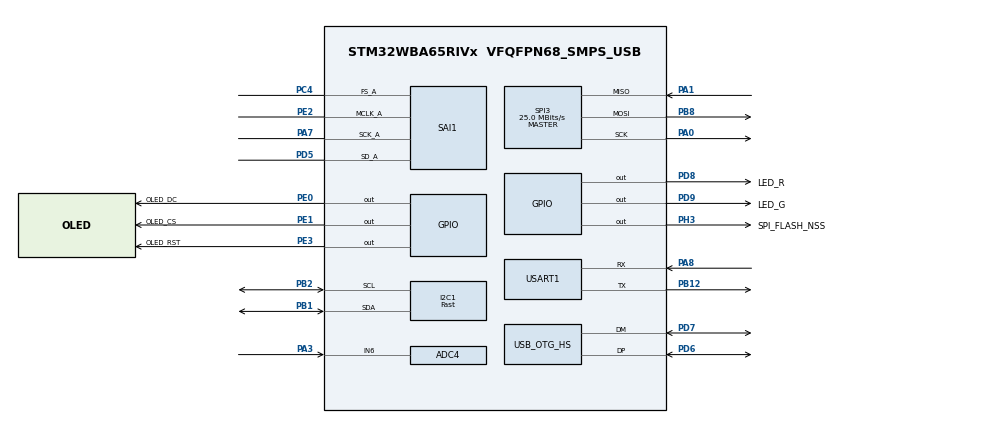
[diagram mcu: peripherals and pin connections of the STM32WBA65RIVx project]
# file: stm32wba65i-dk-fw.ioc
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ADC4.Channel-0\#ChannelRegularConversion=ADC_CHANNEL_6
ADC4.ContinuousConvMode=ENABLE
ADC4.DMAContinuousRequests=ENABLE
ADC4.NbrOfConversionFlag=1
ADC4.OversamplingMode=ENABLE
ADC4.Rank-0\#ChannelRegularConversion=1
ADC4.Ratio=ADC_OVERSAMPLING_RATIO_16
ADC4.RightBitShift=ADC_RIGHTBITSHIFT_4
ADC4.SamplingTime-0\#ChannelRegularConversion=ADC_SAMPLINGTIME_COMMON_1
ADC4.SamplingTimeCommon1=ADC_SAMPLETIME_79CYCLES_5
ADC4.SelectedChannel=ADC_CHANNEL_6
CORTEX_M33_NS.userName=CORTEX_M33
GPDMA1.CIRCULARMODE_GPDMACH0=ENABLE
GPDMA1.CIRCULARMODE_GPDMACH2=ENABLE
GPDMA1.CIRCULARMODE_GPDMACH3=ENABLE
GPDMA1.DESTDATAWIDTH_GPDMACH2=DMA_DEST_DATAWIDTH_HALFWORD
GPDMA1.DESTDATAWIDTH_GPDMACH3=DMA_DEST_DATAWIDTH_HALFWORD
GPDMA1.DESTINC_GPDMACH0=DMA_DINC_INCREMENTED
GPDMA1.DESTINC_GPDMACH1=DMA_DINC_INCREMENTED
GPDMA1.DESTINC_GPDMACH2=DMA_DINC_INCREMENTED
GPDMA1.DIRECTION_GPDMACH1=DMA_PERIPH_TO_MEMORY
GPDMA1.DIRECTION_GPDMACH3=DMA_MEMORY_TO_PERIPH
GPDMA1.DMAHANDLE_GPDMACH3=hdmatx
GPDMA1.IPHANDLE_GPDMACH0-SIMPLEREQUEST_GPDMACH0=__NULL
GPDMA1.IPHANDLE_GPDMACH1-SIMPLEREQUEST_GPDMACH1=__NULL
GPDMA1.IPHANDLE_GPDMACH2-SIMPLEREQUEST_GPDMACH2=__NULL
GPDMA1.IPHANDLE_GPDMACH3-SIMPLEREQUEST_GPDMACH3=__NULL
GPDMA1.REQUEST_GPDMACH0=GPDMA1_REQUEST_USART1_RX
GPDMA1.REQUEST_GPDMACH1=GPDMA1_REQUEST_SPI3_RX
GPDMA1.REQUEST_GPDMACH2=GPDMA1_REQUEST_ADC4
GPDMA1.REQUEST_GPDMACH3=GPDMA1_REQUEST_SAI1_A
GPDMA1.SRCDATAWIDTH_GPDMACH2=DMA_SRC_DATAWIDTH_HALFWORD
GPDMA1.SRCDATAWIDTH_GPDMACH3=DMA_SRC_DATAWIDTH_HALFWORD
GPDMA1.SRCINC_GPDMACH1=DMA_SINC_FIXED
GPDMA1.SRCINC_GPDMACH3=DMA_SINC_INCREMENTED
I2C1.I2C_Speed_Mode=I2C_Fast
I2C1.Timing=0x009034B6
Mcu.Family=STM32WBA
Mcu.Name=STM32WBA65RIVx
Mcu.Package=VFQFPN68_SMPS_USB
NVIC.GPDMA1_Channel1_IRQn=true\:5\:0\:true\:false\:true\:true\:true\:true
NVIC.GPDMA1_Channel3_IRQn=true\:5\:0\:true\:false\:true\:true\:true\:true
NVIC.PriorityGroup=NVIC_PRIORITYGROUP_4
NVIC.SAI1_IRQn=true\:5\:0\:true\:false\:true\:true\:true\:true
NVIC.SPI3_IRQn=true\:5\:0\:true\:false\:true\:true\:true\:true
NVIC.USB_OTG_HS_IRQn=true\:5\:0\:true\:false\:true\:true\:true\:true
OSC_IN.Mode=HSE-External-Oscillator
OSC_IN.Signal=RCC_OSC_IN
OSC_OUT.Mode=HSE-External-Oscillator
OSC_OUT.Signal=RCC_OSC_OUT
PA0.GPIO_Speed=GPIO_SPEED_FREQ_HIGH
PA0.Mode=Full_Duplex_Master
PA0.Signal=SPI3_SCK
PA1.GPIO_Speed=GPIO_SPEED_FREQ_HIGH
PA1.Mode=Full_Duplex_Master
PA1.Signal=SPI3_MISO
PA13(JTSM/SWDIO).Mode=Serial_Wire
PA13(JTSM/SWDIO).Signal=DEBUG_JTMS-SWDIO
PA14(JTCK/SWCLK).Mode=Serial_Wire
PA14(JTCK/SWCLK).Signal=DEBUG_JTCK-SWCLK
PA3.Mode=IN6
PA3.Signal=ADC4_IN6
PA7.Mode=SAI_A_MasterWithClock
PA7.Signal=SAI1_SCK_A
PA8.Mode=Asynchronous
PA8.Signal=USART1_RX
PB1.Mode=I2C
PB1.Signal=I2C1_SDA
PB12.Mode=Asynchronous
PB12.Signal=USART1_TX
PB2.Mode=I2C
PB2.Signal=I2C1_SCL
PB8.GPIO_Speed=GPIO_SPEED_FREQ_HIGH
PB8.Mode=Full_Duplex_Master
PB8.Signal=SPI3_MOSI
PC14-OSC32_IN.Mode=LSE-External-Oscillator
PC14-OSC32_IN.Signal=RCC_OSC32_IN
PC15-OSC32_OUT.Mode=LSE-External-Oscillator
PC15-OSC32_OUT.Signal=RCC_OSC32_OUT
PC4.Mode=SAI_A_MasterWithClock
PC4.Signal=SAI1_FS_A
PD5.GPIO_Speed=GPIO_SPEED_FREQ_HIGH
PD5.Mode=SAI_A_MasterWithClock
PD5.Signal=SAI1_SD_A
PD6.Mode=Internal_Phy_Device
PD6.Signal=USB_OTG_HS_DP
PD7.Mode=Internal_Phy_Device
PD7.Signal=USB_OTG_HS_DM
PD8.GPIO_Label=LED_R
PD8.PinState=GPIO_PIN_SET
PD8.Signal=GPIO_Output
PD9.GPIO_Label=LED_G
PD9.PinState=GPIO_PIN_SET
PD9.Signal=GPIO_Output
PE0.GPIO_Label=OLED_DC
PE0.GPIO_Speed=GPIO_SPEED_FREQ_HIGH
PE0.PinState=GPIO_PIN_SET
PE0.Signal=GPIO_Output
PE1.GPIO_Label=OLED_CS
PE1.GPIO_Speed=GPIO_SPEED_FREQ_HIGH
PE1.PinState=GPIO_PIN_SET
PE1.Signal=GPIO_Output
PE2.Mode=SAI_A_MasterWithClock
PE2.Signal=SAI1_MCLK_A
PE3.GPIO_Label=OLED_RST
PE3.GPIO_Speed=GPIO_SPEED_FREQ_HIGH
PE3.PinState=GPIO_PIN_SET
PE3.Signal=GPIO_Output
PH3-BOOT0.GPIO_Label=SPI_FLASH_NSS
PH3-BOOT0.GPIO_Speed=GPIO_SPEED_FREQ_HIGH
PH3-BOOT0.PinState=GPIO_PIN_SET
PH3-BOOT0.Signal=GPIO_Output
ProjectManager.HeapSize=0x200
ProjectManager.StackSize=0x400
ProjectManager.TargetToolchain=CMake
RCC.ADCFreq_Value=100000000
RCC.AHB5CLKDivider=DIV4
RCC.AHBFreq_Value=100000000
RCC.APB1Freq_Value=100000000
RCC.APB1TimFreq_Value=100000000
RCC.APB2Freq_Value=100000000
RCC.APB2TimFreq_Value=100000000
RCC.CortexFreq_Value=12500000
RCC.HCLKFreq_Value=100000000
RCC.HSE_VALUE=32000000
RCC.HSI_VALUE=16000000
RCC.LSI1_VALUE=32000
RCC.LSI2_VALUE=32000
RCC.PLLFRACN=4096
RCC.PLLM=2
RCC.PLLN=12
RCC.PLLSourceVirtual=RCC_PLLSOURCE_HSE
RCC.SAI1CLockSelection=RCC_SAI1CLKSOURCE_PLL1Q
RCC.SYSCLKFreq_VALUE=100000000
RCC.SYSCLKSourceVirtual=RCC_SYSCLKSOURCE_PLLCLK
RCC.VCOOutputFreq_Value=200000000
SAI1.AudioFrequency-SAI_A_MasterWithClock=SAI_AUDIO_FREQUENCY_16K
SAI1.ErrorAudioFreq-SAI_A_MasterWithClock=1.72 %
SAI1.InitProtocol-SAI_A_MasterWithClock=Enable
SAI1.Instance-SAI_A_MasterWithClock=SAI$Index_Block_A
SAI1.MckOutput=SAI_MCK_OUTPUT_ENABLE
SAI1.NoDivider-SAI_A_MasterWithClock=SAI_MASTERDIVIDER_ENABLE
SAI1.OutputDrive-SAI_A_MasterWithClock=SAI_OUTPUTDRIVE_DISABLE
SAI1.RealAudioFreq-SAI_A_MasterWithClock=16.276 KHz
SAI1.VirtualMode-SAI_A_MasterWithClock=VM_MASTER
SAI1.VirtualProtocol-SAI_A_BASIC=VM_BASIC_PROTOCOL
SPI3.BaudRatePrescaler=SPI_BAUDRATEPRESCALER_4
SPI3.CalculateBaudRate=25.0 MBits/s
SPI3.Direction=SPI_DIRECTION_2LINES
SPI3.FifoThreshold=SPI_FIFO_THRESHOLD_01DATA
SPI3.Mode=SPI_MODE_MASTER
SPI3.VirtualType=VM_MASTER
USART1.VirtualMode-Asynchronous=VM_ASYNC
USB_OTG_HS.RefClockSelection=SYSCFG_OTG_HS_PHY_CLK_SELECT_6
USB_OTG_HS.Sof_enable=DISABLE
USB_OTG_HS.VirtualMode=Device_HS
VP_CORTEX_M33_NS_VS_Hclk.Mode=Hclk_Mode
VP_GPDMA1_VS_GPDMACH0.Mode=SIMPLEREQUEST_GPDMACH0
VP_GPDMA1_VS_GPDMACH1.Mode=SIMPLEREQUEST_GPDMACH1
VP_GPDMA1_VS_GPDMACH2.Mode=SIMPLEREQUEST_GPDMACH2
VP_GPDMA1_VS_GPDMACH3.Mode=SIMPLEREQUEST_GPDMACH3
VP_ICACHE_VS_ICACHE.Mode=DefaultMode
VP_MEMORYMAP_VS_MEMORYMAP.Mode=CurAppReg
VP_PWR_VS_SECSignals.Mode=Security/Privilege
VP_SAI1_VP_$IpInstance_SAIA_SAI_BASIC.Mode=SAI_A_BASIC
board=custom

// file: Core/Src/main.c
/* USER CODE BEGIN Header */
/**
  ******************************************************************************
  * @file           : main.c
  * @brief          : Main program body
  ******************************************************************************
  * @attention
  *
  * Copyright (c) 2025 STMicroelectronics.
  * All rights reserved.
  *
  * This software is licensed under terms that can be found in the LICENSE file
  * in the root directory of this software component.
  * If no LICENSE file comes with this software, it is provided AS-IS.
  *
  ******************************************************************************
  */
/* USER CODE END Header */
#include "main.h"

/* USER CODE BEGIN Includes */
#include "ap.h"
/* USER CODE END Includes */

ADC_HandleTypeDef hadc4;
DMA_NodeTypeDef Node_GPDMA1_Channel2;
DMA_QListTypeDef List_GPDMA1_Channel2;
DMA_HandleTypeDef handle_GPDMA1_Channel2;

I2C_HandleTypeDef hi2c1;

SAI_HandleTypeDef hsai_BlockA1;
DMA_NodeTypeDef Node_GPDMA1_Channel3;
DMA_QListTypeDef List_GPDMA1_Channel3;
DMA_HandleTypeDef handle_GPDMA1_Channel3;

SPI_HandleTypeDef hspi3;
DMA_HandleTypeDef handle_GPDMA1_Channel1;

UART_HandleTypeDef huart1;
DMA_NodeTypeDef Node_GPDMA1_Channel0;
DMA_QListTypeDef List_GPDMA1_Channel0;
DMA_HandleTypeDef handle_GPDMA1_Channel0;

PCD_HandleTypeDef hpcd_USB_OTG_HS;

void SystemClock_Config(void);
static void MX_GPIO_Init(void);
static void MX_GPDMA1_Init(void);
static void MX_ICACHE_Init(void);
static void MX_USART1_UART_Init(void);
static void MX_USB_OTG_HS_PCD_Init(void);
static void MX_SPI3_Init(void);
static void MX_ADC4_Init(void);
static void MX_I2C1_Init(void);
static void MX_SAI1_Init(void);

int main(void)
{

  /* MCU Configuration--------------------------------------------------------*/

  /* Reset of all peripherals, Initializes the Flash interface and the Systick. */
  HAL_Init();

  /* Configure the system clock */
  SystemClock_Config();

  /* Initialize all configured peripherals */
  MX_GPIO_Init();
  MX_GPDMA1_Init();
  MX_ICACHE_Init();
  MX_USART1_UART_Init();
  MX_USB_OTG_HS_PCD_Init();
  MX_SPI3_Init();
  MX_ADC4_Init();
  MX_I2C1_Init();
  MX_SAI1_Init();
  /* USER CODE BEGIN 2 */

  hwInit();
  apInit();
  apMain();

  /* USER CODE END 2 */

  /* Infinite loop */
  while (1)
  {

  }
}

void SystemClock_Config(void)
{
  RCC_OscInitTypeDef RCC_OscInitStruct = {0};
  RCC_ClkInitTypeDef RCC_ClkInitStruct = {0};

  /** Supply configuration update enable
  */
  HAL_PWREx_ConfigSupply(PWR_LDO_SUPPLY);

  /** Configure the main internal regulator output voltage
  */
  if (HAL_PWREx_ControlVoltageScaling(PWR_REGULATOR_VOLTAGE_SCALE1) != HAL_OK)
  {
    Error_Handler();
  }

  /** Initializes the CPU, AHB and APB busses clocks
  */
  RCC_OscInitStruct.OscillatorType = RCC_OSCILLATORTYPE_HSI|RCC_OSCILLATORTYPE_HSE;
  RCC_OscInitStruct.HSEState = RCC_HSE_ON;
  RCC_OscInitStruct.HSEDiv = RCC_HSE_DIV1;
  RCC_OscInitStruct.HSIState = RCC_HSI_ON;
  RCC_OscInitStruct.HSICalibrationValue = RCC_HSICALIBRATION_DEFAULT;
  RCC_OscInitStruct.PLL1.PLLState = RCC_PLL_ON;
  RCC_OscInitStruct.PLL1.PLLSource = RCC_PLLSOURCE_HSE;
  RCC_OscInitStruct.PLL1.PLLM = 2;
  RCC_OscInitStruct.PLL1.PLLN = 12;
  RCC_OscInitStruct.PLL1.PLLP = 2;
  RCC_OscInitStruct.PLL1.PLLQ = 2;
  RCC_OscInitStruct.PLL1.PLLR = 2;
  RCC_OscInitStruct.PLL1.PLLFractional = 4096;
  if (HAL_RCC_OscConfig(&RCC_OscInitStruct) != HAL_OK)
  {
    Error_Handler();
  }

  /** Initializes the CPU, AHB and APB busses clocks
  */
  RCC_ClkInitStruct.ClockType = RCC_CLOCKTYPE_HCLK|RCC_CLOCKTYPE_SYSCLK
                              |RCC_CLOCKTYPE_PCLK1|RCC_CLOCKTYPE_PCLK2
                              |RCC_CLOCKTYPE_PCLK7|RCC_CLOCKTYPE_HCLK5;
  RCC_ClkInitStruct.SYSCLKSource = RCC_SYSCLKSOURCE_PLLCLK;
  RCC_ClkInitStruct.AHBCLKDivider = RCC_SYSCLK_DIV1;
  RCC_ClkInitStruct.APB1CLKDivider = RCC_HCLK_DIV1;
  RCC_ClkInitStruct.APB2CLKDivider = RCC_HCLK_DIV1;
  RCC_ClkInitStruct.APB7CLKDivider = RCC_HCLK_DIV1;
  RCC_ClkInitStruct.AHB5_PLL1_CLKDivider = RCC_SYSCLK_PLL1_DIV4;
  RCC_ClkInitStruct.AHB5_HSEHSI_CLKDivider = RCC_SYSCLK_HSEHSI_DIV1;

  if (HAL_RCC_ClockConfig(&RCC_ClkInitStruct, FLASH_LATENCY_3) != HAL_OK)
  {
    Error_Handler();
  }
}

static void MX_ADC4_Init(void)
{

  ADC_ChannelConfTypeDef sConfig = {0};

  /** Common config
  */
  hadc4.Instance = ADC4;
  hadc4.Init.ClockPrescaler = ADC_CLOCK_ASYNC_DIV1;
  hadc4.Init.Resolution = ADC_RESOLUTION_12B;
  hadc4.Init.DataAlign = ADC_DATAALIGN_RIGHT;
  hadc4.Init.ScanConvMode = ADC_SCAN_DISABLE;
  hadc4.Init.EOCSelection = ADC_EOC_SINGLE_CONV;
  hadc4.Init.LowPowerAutoPowerOff = DISABLE;
  hadc4.Init.LowPowerAutonomousDPD = ADC_LP_AUTONOMOUS_DPD_DISABLE;
  hadc4.Init.LowPowerAutoWait = DISABLE;
  hadc4.Init.ContinuousConvMode = ENABLE;
  hadc4.Init.NbrOfConversion = 1;
  hadc4.Init.ExternalTrigConv = ADC_SOFTWARE_START;
  hadc4.Init.ExternalTrigConvEdge = ADC_EXTERNALTRIGCONVEDGE_NONE;
  hadc4.Init.DMAContinuousRequests = ENABLE;
  hadc4.Init.TriggerFrequencyMode = ADC_TRIGGER_FREQ_LOW;
  hadc4.Init.Overrun = ADC_OVR_DATA_PRESERVED;
  hadc4.Init.SamplingTimeCommon1 = ADC_SAMPLETIME_79CYCLES_5;
  hadc4.Init.SamplingTimeCommon2 = ADC_SAMPLETIME_1CYCLE_5;
  hadc4.Init.OversamplingMode = ENABLE;
  hadc4.Init.Oversampling.Ratio = ADC_OVERSAMPLING_RATIO_16;
  hadc4.Init.Oversampling.RightBitShift = ADC_RIGHTBITSHIFT_4;
  hadc4.Init.Oversampling.TriggeredMode = ADC_TRIGGEREDMODE_SINGLE_TRIGGER;
  if (HAL_ADC_Init(&hadc4) != HAL_OK)
  {
    Error_Handler();
  }

  /** Configure Regular Channel
  */
  sConfig.Channel = ADC_CHANNEL_6;
  sConfig.Rank = ADC_REGULAR_RANK_1;
  sConfig.SamplingTime = ADC_SAMPLINGTIME_COMMON_1;
  if (HAL_ADC_ConfigChannel(&hadc4, &sConfig) != HAL_OK)
  {
    Error_Handler();
  }

}

static void MX_GPDMA1_Init(void)
{

  /* Peripheral clock enable */
  __HAL_RCC_GPDMA1_CLK_ENABLE();

  /* GPDMA1 interrupt Init */
    HAL_NVIC_SetPriority(GPDMA1_Channel1_IRQn, 5, 0);
    HAL_NVIC_EnableIRQ(GPDMA1_Channel1_IRQn);
    HAL_NVIC_SetPriority(GPDMA1_Channel3_IRQn, 5, 0);
    HAL_NVIC_EnableIRQ(GPDMA1_Channel3_IRQn);

}

static void MX_I2C1_Init(void)
{

  hi2c1.Instance = I2C1;
  hi2c1.Init.Timing = 0x009034B6;
  hi2c1.Init.OwnAddress1 = 0;
  hi2c1.Init.AddressingMode = I2C_ADDRESSINGMODE_7BIT;
  hi2c1.Init.DualAddressMode = I2C_DUALADDRESS_DISABLE;
  hi2c1.Init.OwnAddress2 = 0;
  hi2c1.Init.OwnAddress2Masks = I2C_OA2_NOMASK;
  hi2c1.Init.GeneralCallMode = I2C_GENERALCALL_DISABLE;
  hi2c1.Init.NoStretchMode = I2C_NOSTRETCH_DISABLE;
  if (HAL_I2C_Init(&hi2c1) != HAL_OK)
  {
    Error_Handler();
  }

  /** Configure Analogue filter
  */
  if (HAL_I2CEx_ConfigAnalogFilter(&hi2c1, I2C_ANALOGFILTER_ENABLE) != HAL_OK)
  {
    Error_Handler();
  }

  /** Configure Digital filter
  */
  if (HAL_I2CEx_ConfigDigitalFilter(&hi2c1, 0) != HAL_OK)
  {
    Error_Handler();
  }

}

static void MX_ICACHE_Init(void)
{

  /** Enable instruction cache (default 2-ways set associative cache)
  */
  if (HAL_ICACHE_Enable() != HAL_OK)
  {
    Error_Handler();
  }

}

static void MX_SAI1_Init(void)
{

  hsai_BlockA1.Instance = SAI1_Block_A;
  hsai_BlockA1.Init.AudioMode = SAI_MODEMASTER_TX;
  hsai_BlockA1.Init.Synchro = SAI_ASYNCHRONOUS;
  hsai_BlockA1.Init.OutputDrive = SAI_OUTPUTDRIVE_DISABLE;
  hsai_BlockA1.Init.NoDivider = SAI_MASTERDIVIDER_ENABLE;
  hsai_BlockA1.Init.FIFOThreshold = SAI_FIFOTHRESHOLD_EMPTY;
  hsai_BlockA1.Init.AudioFrequency = SAI_AUDIO_FREQUENCY_16K;
  hsai_BlockA1.Init.SynchroExt = SAI_SYNCEXT_DISABLE;
  hsai_BlockA1.Init.MckOutput = SAI_MCK_OUTPUT_ENABLE;
  hsai_BlockA1.Init.MonoStereoMode = SAI_STEREOMODE;
  hsai_BlockA1.Init.CompandingMode = SAI_NOCOMPANDING;
  hsai_BlockA1.Init.TriState = SAI_OUTPUT_NOTRELEASED;
  if (HAL_SAI_InitProtocol(&hsai_BlockA1, SAI_I2S_STANDARD, SAI_PROTOCOL_DATASIZE_16BIT, 2) != HAL_OK)
  {
    Error_Handler();
  }

}

static void MX_SPI3_Init(void)
{

  SPI_AutonomousModeConfTypeDef HAL_SPI_AutonomousMode_Cfg_Struct = {0};

  /* SPI3 parameter configuration*/
  hspi3.Instance = SPI3;
  hspi3.Init.Mode = SPI_MODE_MASTER;
  hspi3.Init.Direction = SPI_DIRECTION_2LINES;
  hspi3.Init.DataSize = SPI_DATASIZE_8BIT;
  hspi3.Init.CLKPolarity = SPI_POLARITY_LOW;
  hspi3.Init.CLKPhase = SPI_PHASE_1EDGE;
  hspi3.Init.NSS = SPI_NSS_SOFT;
  hspi3.Init.BaudRatePrescaler = SPI_BAUDRATEPRESCALER_4;
  hspi3.Init.FirstBit = SPI_FIRSTBIT_MSB;
  hspi3.Init.TIMode = SPI_TIMODE_DISABLE;
  hspi3.Init.CRCCalculation = SPI_CRCCALCULATION_DISABLE;
  hspi3.Init.CRCPolynomial = 0x7;
  hspi3.Init.NSSPMode = SPI_NSS_PULSE_ENABLE;
  hspi3.Init.NSSPolarity = SPI_NSS_POLARITY_LOW;
  hspi3.Init.FifoThreshold = SPI_FIFO_THRESHOLD_01DATA;
  hspi3.Init.MasterSSIdleness = SPI_MASTER_SS_IDLENESS_00CYCLE;
  hspi3.Init.MasterInterDataIdleness = SPI_MASTER_INTERDATA_IDLENESS_00CYCLE;
  hspi3.Init.MasterReceiverAutoSusp = SPI_MASTER_RX_AUTOSUSP_DISABLE;
  hspi3.Init.MasterKeepIOState = SPI_MASTER_KEEP_IO_STATE_DISABLE;
  hspi3.Init.IOSwap = SPI_IO_SWAP_DISABLE;
  hspi3.Init.ReadyMasterManagement = SPI_RDY_MASTER_MANAGEMENT_INTERNALLY;
  hspi3.Init.ReadyPolarity = SPI_RDY_POLARITY_HIGH;
  if (HAL_SPI_Init(&hspi3) != HAL_OK)
  {
    Error_Handler();
  }
  HAL_SPI_AutonomousMode_Cfg_Struct.TriggerState = SPI_AUTO_MODE_DISABLE;
  if (HAL_SPIEx_SetConfigAutonomousMode(&hspi3, &HAL_SPI_AutonomousMode_Cfg_Struct) != HAL_OK)
  {
    Error_Handler();
  }

}

static void MX_USART1_UART_Init(void)
{

  huart1.Instance = USART1;
  huart1.Init.BaudRate = 115200;
  huart1.Init.WordLength = UART_WORDLENGTH_8B;
  huart1.Init.StopBits = UART_STOPBITS_1;
  huart1.Init.Parity = UART_PARITY_NONE;
  huart1.Init.Mode = UART_MODE_TX_RX;
  huart1.Init.HwFlowCtl = UART_HWCONTROL_NONE;
  huart1.Init.OverSampling = UART_OVERSAMPLING_16;
  huart1.Init.OneBitSampling = UART_ONE_BIT_SAMPLE_DISABLE;
  huart1.Init.ClockPrescaler = UART_PRESCALER_DIV1;
  huart1.AdvancedInit.AdvFeatureInit = UART_ADVFEATURE_NO_INIT;
  if (HAL_UART_Init(&huart1) != HAL_OK)
  {
    Error_Handler();
  }
  if (HAL_UARTEx_SetTxFifoThreshold(&huart1, UART_TXFIFO_THRESHOLD_1_8) != HAL_OK)
  {
    Error_Handler();
  }
  if (HAL_UARTEx_SetRxFifoThreshold(&huart1, UART_RXFIFO_THRESHOLD_1_8) != HAL_OK)
  {
    Error_Handler();
  }
  if (HAL_UARTEx_DisableFifoMode(&huart1) != HAL_OK)
  {
    Error_Handler();
  }

}

static void MX_USB_OTG_HS_PCD_Init(void)
{

  hpcd_USB_OTG_HS.Instance = USB_OTG_HS;
  hpcd_USB_OTG_HS.Init.dev_endpoints = 9;
  hpcd_USB_OTG_HS.Init.speed = PCD_SPEED_HIGH;
  hpcd_USB_OTG_HS.Init.phy_itface = USB_OTG_HS_EMBEDDED_PHY;
  hpcd_USB_OTG_HS.Init.Sof_enable = DISABLE;
  hpcd_USB_OTG_HS.Init.low_power_enable = DISABLE;
  hpcd_USB_OTG_HS.Init.lpm_enable = DISABLE;
  hpcd_USB_OTG_HS.Init.use_dedicated_ep1 = DISABLE;
  hpcd_USB_OTG_HS.Init.vbus_sensing_enable = DISABLE;
  hpcd_USB_OTG_HS.Init.dma_enable = DISABLE;
  if (HAL_PCD_Init(&hpcd_USB_OTG_HS) != HAL_OK)
  {
    Error_Handler();
  }

}

static void MX_GPIO_Init(void)
{
  GPIO_InitTypeDef GPIO_InitStruct = {0};

  /* GPIO Ports Clock Enable */
  __HAL_RCC_GPIOB_CLK_ENABLE();
  __HAL_RCC_GPIOA_CLK_ENABLE();
  __HAL_RCC_GPIOD_CLK_ENABLE();
  __HAL_RCC_GPIOC_CLK_ENABLE();
  __HAL_RCC_GPIOE_CLK_ENABLE();
  __HAL_RCC_GPIOH_CLK_ENABLE();

  /*Configure GPIO pin Output Level */
  HAL_GPIO_WritePin(GPIOD, LED_G_Pin|LED_R_Pin, GPIO_PIN_SET);

  /*Configure GPIO pin Output Level */
  HAL_GPIO_WritePin(GPIOE, OLED_RST_Pin|OLED_CS_Pin|OLED_DC_Pin, GPIO_PIN_SET);

  /*Configure GPIO pin Output Level */
  HAL_GPIO_WritePin(SPI_FLASH_NSS_GPIO_Port, SPI_FLASH_NSS_Pin, GPIO_PIN_SET);

  /*Configure GPIO pins : LED_G_Pin LED_R_Pin */
  GPIO_InitStruct.Pin = LED_G_Pin|LED_R_Pin;
  GPIO_InitStruct.Mode = GPIO_MODE_OUTPUT_PP;
  GPIO_InitStruct.Pull = GPIO_NOPULL;
  GPIO_InitStruct.Speed = GPIO_SPEED_FREQ_LOW;
  HAL_GPIO_Init(GPIOD, &GPIO_InitStruct);

  /*Configure GPIO pins : OLED_RST_Pin OLED_CS_Pin OLED_DC_Pin */
  GPIO_InitStruct.Pin = OLED_RST_Pin|OLED_CS_Pin|OLED_DC_Pin;
  GPIO_InitStruct.Mode = GPIO_MODE_OUTPUT_PP;
  GPIO_InitStruct.Pull = GPIO_NOPULL;
  GPIO_InitStruct.Speed = GPIO_SPEED_FREQ_HIGH;
  HAL_GPIO_Init(GPIOE, &GPIO_InitStruct);

  /*Configure GPIO pin : SPI_FLASH_NSS_Pin */
  GPIO_InitStruct.Pin = SPI_FLASH_NSS_Pin;
  GPIO_InitStruct.Mode = GPIO_MODE_OUTPUT_PP;
  GPIO_InitStruct.Pull = GPIO_NOPULL;
  GPIO_InitStruct.Speed = GPIO_SPEED_FREQ_HIGH;
  HAL_GPIO_Init(SPI_FLASH_NSS_GPIO_Port, &GPIO_InitStruct);

}

void Error_Handler(void)
{
  __disable_irq();
  while (1)
  {
  }
}
